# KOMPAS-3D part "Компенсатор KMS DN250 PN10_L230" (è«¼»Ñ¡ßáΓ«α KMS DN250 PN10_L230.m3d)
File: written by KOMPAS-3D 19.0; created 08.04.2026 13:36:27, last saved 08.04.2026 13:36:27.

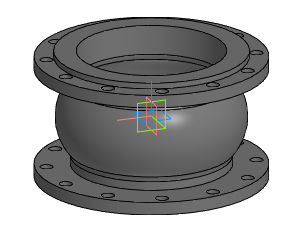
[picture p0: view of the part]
Document properties: Автор: Энергия; Полное имя файла: Z:\3.Личные\kachalov\3d для проектировщиков\7.1 Компенсатор\stp_Компенсатор KSM\Компенсатор KMS DN250 PN10_L230.m3d

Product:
- Part/product: Компенсатор KMS DN250 PN10_L230

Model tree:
1. Операция без истории:1  (labels: Компенсатор KMS DN250 PN10_L230)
